VERSION 5.8 ;
BUSBITCHARS "[]" ;
DIVIDERCHAR "/" ;
UNITS
    DATABASE MICRONS 1000 ;
END UNITS

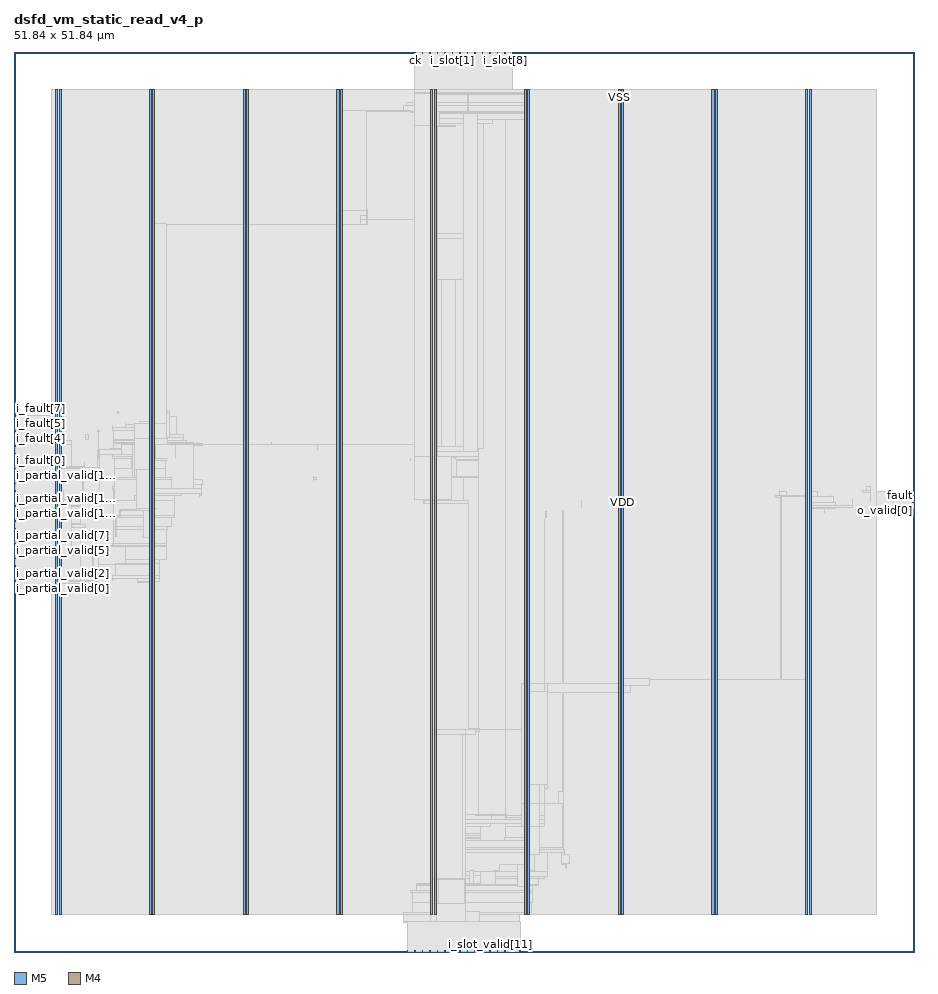
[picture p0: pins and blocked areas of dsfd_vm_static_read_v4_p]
MACRO dsfd_vm_static_read_v4_p
  FOREIGN dsfd_vm_static_read_v4_p 0 0 ;
  CLASS BLOCK ;
  SIZE 51.84 BY 51.84 ;
  PIN ck
    DIRECTION INPUT ;
    USE SIGNAL ;
    PORT
      LAYER M5 ;
        RECT  23.088 51.756 23.112 51.84 ;
    END
  END ck
  PIN fault
    DIRECTION OUTPUT ;
    USE SIGNAL ;
    PORT
      LAYER M4 ;
        RECT  51.756 26.304 51.84 26.328 ;
    END
  END fault
  PIN i_expected[0]
    DIRECTION INPUT ;
    USE SIGNAL ;
    PORT
      LAYER M5 ;
        RECT  23.952 51.756 23.976 51.84 ;
    END
  END i_expected[0]
  PIN i_expected[1]
    DIRECTION INPUT ;
    USE SIGNAL ;
    PORT
      LAYER M5 ;
        RECT  24.384 51.756 24.408 51.84 ;
    END
  END i_expected[1]
  PIN i_fault[0]
    DIRECTION INPUT ;
    USE SIGNAL ;
    PORT
      LAYER M4 ;
        RECT  0 27.84 0.084 27.864 ;
    END
  END i_fault[0]
  PIN i_fault[1]
    DIRECTION INPUT ;
    USE SIGNAL ;
    PORT
      LAYER M4 ;
        RECT  0 28.272 0.084 28.296 ;
    END
  END i_fault[1]
  PIN i_fault[2]
    DIRECTION INPUT ;
    USE SIGNAL ;
    PORT
      LAYER M4 ;
        RECT  0 28.704 0.084 28.728 ;
    END
  END i_fault[2]
  PIN i_fault[3]
    DIRECTION INPUT ;
    USE SIGNAL ;
    PORT
      LAYER M4 ;
        RECT  0 29.136 0.084 29.16 ;
    END
  END i_fault[3]
  PIN i_fault[4]
    DIRECTION INPUT ;
    USE SIGNAL ;
    PORT
      LAYER M4 ;
        RECT  0 29.568 0.084 29.592 ;
    END
  END i_fault[4]
  PIN i_fault[5]
    DIRECTION INPUT ;
    USE SIGNAL ;
    PORT
      LAYER M4 ;
        RECT  0 30 0.084 30.024 ;
    END
  END i_fault[5]
  PIN i_fault[6]
    DIRECTION INPUT ;
    USE SIGNAL ;
    PORT
      LAYER M4 ;
        RECT  0 30.432 0.084 30.456 ;
    END
  END i_fault[6]
  PIN i_fault[7]
    DIRECTION INPUT ;
    USE SIGNAL ;
    PORT
      LAYER M4 ;
        RECT  0 30.864 0.084 30.888 ;
    END
  END i_fault[7]
  PIN i_partial_valid[0]
    DIRECTION INPUT ;
    USE SIGNAL ;
    PORT
      LAYER M4 ;
        RECT  0 20.928 0.084 20.952 ;
    END
  END i_partial_valid[0]
  PIN i_partial_valid[10]
    DIRECTION INPUT ;
    USE SIGNAL ;
    PORT
      LAYER M4 ;
        RECT  0 25.248 0.084 25.272 ;
    END
  END i_partial_valid[10]
  PIN i_partial_valid[11]
    DIRECTION INPUT ;
    USE SIGNAL ;
    PORT
      LAYER M4 ;
        RECT  0 25.68 0.084 25.704 ;
    END
  END i_partial_valid[11]
  PIN i_partial_valid[12]
    DIRECTION INPUT ;
    USE SIGNAL ;
    PORT
      LAYER M4 ;
        RECT  0 26.112 0.084 26.136 ;
    END
  END i_partial_valid[12]
  PIN i_partial_valid[13]
    DIRECTION INPUT ;
    USE SIGNAL ;
    PORT
      LAYER M4 ;
        RECT  0 26.544 0.084 26.568 ;
    END
  END i_partial_valid[13]
  PIN i_partial_valid[14]
    DIRECTION INPUT ;
    USE SIGNAL ;
    PORT
      LAYER M4 ;
        RECT  0 26.976 0.084 27 ;
    END
  END i_partial_valid[14]
  PIN i_partial_valid[15]
    DIRECTION INPUT ;
    USE SIGNAL ;
    PORT
      LAYER M4 ;
        RECT  0 27.408 0.084 27.432 ;
    END
  END i_partial_valid[15]
  PIN i_partial_valid[1]
    DIRECTION INPUT ;
    USE SIGNAL ;
    PORT
      LAYER M4 ;
        RECT  0 21.36 0.084 21.384 ;
    END
  END i_partial_valid[1]
  PIN i_partial_valid[2]
    DIRECTION INPUT ;
    USE SIGNAL ;
    PORT
      LAYER M4 ;
        RECT  0 21.792 0.084 21.816 ;
    END
  END i_partial_valid[2]
  PIN i_partial_valid[3]
    DIRECTION INPUT ;
    USE SIGNAL ;
    PORT
      LAYER M4 ;
        RECT  0 22.224 0.084 22.248 ;
    END
  END i_partial_valid[3]
  PIN i_partial_valid[4]
    DIRECTION INPUT ;
    USE SIGNAL ;
    PORT
      LAYER M4 ;
        RECT  0 22.656 0.084 22.68 ;
    END
  END i_partial_valid[4]
  PIN i_partial_valid[5]
    DIRECTION INPUT ;
    USE SIGNAL ;
    PORT
      LAYER M4 ;
        RECT  0 23.088 0.084 23.112 ;
    END
  END i_partial_valid[5]
  PIN i_partial_valid[6]
    DIRECTION INPUT ;
    USE SIGNAL ;
    PORT
      LAYER M4 ;
        RECT  0 23.52 0.084 23.544 ;
    END
  END i_partial_valid[6]
  PIN i_partial_valid[7]
    DIRECTION INPUT ;
    USE SIGNAL ;
    PORT
      LAYER M4 ;
        RECT  0 23.952 0.084 23.976 ;
    END
  END i_partial_valid[7]
  PIN i_partial_valid[8]
    DIRECTION INPUT ;
    USE SIGNAL ;
    PORT
      LAYER M4 ;
        RECT  0 24.384 0.084 24.408 ;
    END
  END i_partial_valid[8]
  PIN i_partial_valid[9]
    DIRECTION INPUT ;
    USE SIGNAL ;
    PORT
      LAYER M4 ;
        RECT  0 24.816 0.084 24.84 ;
    END
  END i_partial_valid[9]
  PIN i_slot[0]
    DIRECTION INPUT ;
    USE SIGNAL ;
    PORT
      LAYER M5 ;
        RECT  24.816 51.756 24.84 51.84 ;
    END
  END i_slot[0]
  PIN i_slot[1]
    DIRECTION INPUT ;
    USE SIGNAL ;
    PORT
      LAYER M5 ;
        RECT  25.248 51.756 25.272 51.84 ;
    END
  END i_slot[1]
  PIN i_slot[2]
    DIRECTION INPUT ;
    USE SIGNAL ;
    PORT
      LAYER M5 ;
        RECT  25.68 51.756 25.704 51.84 ;
    END
  END i_slot[2]
  PIN i_slot[3]
    DIRECTION INPUT ;
    USE SIGNAL ;
    PORT
      LAYER M5 ;
        RECT  26.112 51.756 26.136 51.84 ;
    END
  END i_slot[3]
  PIN i_slot[4]
    DIRECTION INPUT ;
    USE SIGNAL ;
    PORT
      LAYER M5 ;
        RECT  26.544 51.756 26.568 51.84 ;
    END
  END i_slot[4]
  PIN i_slot[5]
    DIRECTION INPUT ;
    USE SIGNAL ;
    PORT
      LAYER M5 ;
        RECT  26.976 51.756 27 51.84 ;
    END
  END i_slot[5]
  PIN i_slot[6]
    DIRECTION INPUT ;
    USE SIGNAL ;
    PORT
      LAYER M5 ;
        RECT  27.408 51.756 27.432 51.84 ;
    END
  END i_slot[6]
  PIN i_slot[7]
    DIRECTION INPUT ;
    USE SIGNAL ;
    PORT
      LAYER M5 ;
        RECT  27.84 51.756 27.864 51.84 ;
    END
  END i_slot[7]
  PIN i_slot[8]
    DIRECTION INPUT ;
    USE SIGNAL ;
    PORT
      LAYER M5 ;
        RECT  28.272 51.756 28.296 51.84 ;
    END
  END i_slot[8]
  PIN i_slot[9]
    DIRECTION INPUT ;
    USE SIGNAL ;
    PORT
      LAYER M5 ;
        RECT  28.704 51.756 28.728 51.84 ;
    END
  END i_slot[9]
  PIN i_slot_valid[0]
    DIRECTION INPUT ;
    USE SIGNAL ;
    PORT
      LAYER M5 ;
        RECT  22.656 0 22.68 0.084 ;
    END
  END i_slot_valid[0]
  PIN i_slot_valid[10]
    DIRECTION INPUT ;
    USE SIGNAL ;
    PORT
      LAYER M5 ;
        RECT  26.976 0 27 0.084 ;
    END
  END i_slot_valid[10]
  PIN i_slot_valid[11]
    DIRECTION INPUT ;
    USE SIGNAL ;
    PORT
      LAYER M5 ;
        RECT  27.408 0 27.432 0.084 ;
    END
  END i_slot_valid[11]
  PIN i_slot_valid[12]
    DIRECTION INPUT ;
    USE SIGNAL ;
    PORT
      LAYER M5 ;
        RECT  27.84 0 27.864 0.084 ;
    END
  END i_slot_valid[12]
  PIN i_slot_valid[13]
    DIRECTION INPUT ;
    USE SIGNAL ;
    PORT
      LAYER M5 ;
        RECT  28.272 0 28.296 0.084 ;
    END
  END i_slot_valid[13]
  PIN i_slot_valid[14]
    DIRECTION INPUT ;
    USE SIGNAL ;
    PORT
      LAYER M5 ;
        RECT  28.704 0 28.728 0.084 ;
    END
  END i_slot_valid[14]
  PIN i_slot_valid[15]
    DIRECTION INPUT ;
    USE SIGNAL ;
    PORT
      LAYER M5 ;
        RECT  29.136 0 29.16 0.084 ;
    END
  END i_slot_valid[15]
  PIN i_slot_valid[1]
    DIRECTION INPUT ;
    USE SIGNAL ;
    PORT
      LAYER M5 ;
        RECT  23.088 0 23.112 0.084 ;
    END
  END i_slot_valid[1]
  PIN i_slot_valid[2]
    DIRECTION INPUT ;
    USE SIGNAL ;
    PORT
      LAYER M5 ;
        RECT  23.52 0 23.544 0.084 ;
    END
  END i_slot_valid[2]
  PIN i_slot_valid[3]
    DIRECTION INPUT ;
    USE SIGNAL ;
    PORT
      LAYER M5 ;
        RECT  23.952 0 23.976 0.084 ;
    END
  END i_slot_valid[3]
  PIN i_slot_valid[4]
    DIRECTION INPUT ;
    USE SIGNAL ;
    PORT
      LAYER M5 ;
        RECT  24.384 0 24.408 0.084 ;
    END
  END i_slot_valid[4]
  PIN i_slot_valid[5]
    DIRECTION INPUT ;
    USE SIGNAL ;
    PORT
      LAYER M5 ;
        RECT  24.816 0 24.84 0.084 ;
    END
  END i_slot_valid[5]
  PIN i_slot_valid[6]
    DIRECTION INPUT ;
    USE SIGNAL ;
    PORT
      LAYER M5 ;
        RECT  25.248 0 25.272 0.084 ;
    END
  END i_slot_valid[6]
  PIN i_slot_valid[7]
    DIRECTION INPUT ;
    USE SIGNAL ;
    PORT
      LAYER M5 ;
        RECT  25.68 0 25.704 0.084 ;
    END
  END i_slot_valid[7]
  PIN i_slot_valid[8]
    DIRECTION INPUT ;
    USE SIGNAL ;
    PORT
      LAYER M5 ;
        RECT  26.112 0 26.136 0.084 ;
    END
  END i_slot_valid[8]
  PIN i_slot_valid[9]
    DIRECTION INPUT ;
    USE SIGNAL ;
    PORT
      LAYER M5 ;
        RECT  26.544 0 26.568 0.084 ;
    END
  END i_slot_valid[9]
  PIN o_valid[0]
    DIRECTION OUTPUT ;
    USE SIGNAL ;
    PORT
      LAYER M4 ;
        RECT  51.756 25.44 51.84 25.464 ;
    END
  END o_valid[0]
  PIN o_valid[1]
    DIRECTION OUTPUT ;
    USE SIGNAL ;
    PORT
      LAYER M4 ;
        RECT  51.756 25.872 51.84 25.896 ;
    END
  END o_valid[1]
  PIN rst_n
    DIRECTION INPUT ;
    USE SIGNAL ;
    PORT
      LAYER M5 ;
        RECT  23.52 51.756 23.544 51.84 ;
    END
  END rst_n
  PIN VDD
    DIRECTION INOUT ;
    USE POWER ;
    PORT
      LAYER M5 ;
        RECT  45.792 2.151 45.912 49.689 ;
        RECT  40.392 2.151 40.512 49.689 ;
        RECT  34.992 2.151 35.112 49.689 ;
        RECT  29.592 2.151 29.712 49.689 ;
        RECT  24.192 2.151 24.312 49.689 ;
        RECT  18.792 2.151 18.912 49.689 ;
        RECT  13.392 2.151 13.512 49.689 ;
        RECT  7.992 2.151 8.112 49.689 ;
        RECT  2.592 2.151 2.712 49.689 ;
    END
  END VDD
  PIN VSS
    DIRECTION INOUT ;
    USE GROUND ;
    PORT
      LAYER M5 ;
        RECT  45.6 2.137 45.72 49.703 ;
        RECT  40.2 2.137 40.32 49.703 ;
        RECT  34.8 2.137 34.92 49.703 ;
        RECT  29.4 2.137 29.52 49.703 ;
        RECT  24 2.137 24.12 49.703 ;
        RECT  18.6 2.137 18.72 49.703 ;
        RECT  13.2 2.137 13.32 49.703 ;
        RECT  7.8 2.137 7.92 49.703 ;
        RECT  2.4 2.137 2.52 49.703 ;
    END
  END VSS
  # OT_OBS_CLOSED layer=M5 d_um=1.536 added=10
  OBS
    LAYER RVTN ;
     RECT  2.16 2.16 49.68 2.295 ;
     RECT  2.16 2.565 49.68 2.835 ;
     RECT  2.16 3.105 49.68 3.375 ;
     RECT  2.16 3.645 49.68 3.915 ;
     RECT  2.16 4.185 49.68 4.455 ;
     RECT  2.16 4.725 49.68 4.995 ;
     RECT  2.16 5.265 49.68 5.535 ;
     RECT  2.16 5.805 49.68 6.075 ;
     RECT  2.16 6.345 49.68 6.615 ;
     RECT  2.16 6.885 49.68 7.155 ;
     RECT  2.16 7.425 49.68 7.695 ;
     RECT  2.16 7.965 49.68 8.235 ;
     RECT  2.16 8.505 49.68 8.775 ;
     RECT  2.16 9.045 49.68 9.315 ;
     RECT  2.16 9.585 49.68 9.855 ;
     RECT  2.16 10.125 49.68 10.395 ;
     RECT  2.16 10.665 49.68 10.935 ;
     RECT  2.16 11.205 49.68 11.475 ;
     RECT  2.16 11.745 49.68 12.015 ;
     RECT  2.16 12.285 49.68 12.555 ;
     RECT  2.16 12.825 49.68 13.095 ;
     RECT  2.16 13.365 49.68 13.635 ;
     RECT  2.16 13.905 49.68 14.175 ;
     RECT  2.16 14.445 49.68 14.715 ;
     RECT  2.16 14.985 49.68 15.255 ;
     RECT  2.16 15.525 49.68 15.795 ;
     RECT  2.16 16.065 49.68 16.335 ;
     RECT  2.16 16.605 49.68 16.875 ;
     RECT  2.16 17.145 49.68 17.415 ;
     RECT  2.16 17.685 49.68 17.955 ;
     RECT  2.16 18.225 49.68 18.495 ;
     RECT  2.16 18.765 49.68 19.035 ;
     RECT  2.16 19.305 49.68 19.575 ;
     RECT  2.16 19.845 49.68 20.115 ;
     RECT  2.16 20.385 49.68 20.655 ;
     RECT  2.16 20.925 49.68 21.195 ;
     RECT  2.16 21.465 49.68 21.735 ;
     RECT  2.16 22.005 49.68 22.275 ;
     RECT  2.16 22.545 49.68 22.815 ;
     RECT  2.16 23.085 49.68 23.355 ;
     RECT  2.16 23.625 49.68 23.895 ;
     RECT  2.16 24.165 49.68 24.435 ;
     RECT  2.16 24.705 49.68 24.975 ;
     RECT  2.16 25.245 49.68 25.515 ;
     RECT  2.16 25.785 49.68 26.055 ;
     RECT  2.16 26.325 49.68 26.595 ;
     RECT  2.16 26.865 49.68 27.135 ;
     RECT  2.16 27.405 49.68 27.675 ;
     RECT  2.16 27.945 49.68 28.215 ;
     RECT  2.16 28.485 49.68 28.755 ;
     RECT  2.16 29.025 49.68 29.295 ;
     RECT  2.16 29.565 49.68 29.835 ;
     RECT  2.16 30.105 49.68 30.375 ;
     RECT  2.16 30.645 49.68 30.915 ;
     RECT  2.16 31.185 49.68 31.455 ;
     RECT  2.16 31.725 49.68 31.995 ;
     RECT  2.16 32.265 49.68 32.535 ;
     RECT  2.16 32.805 49.68 33.075 ;
     RECT  2.16 33.345 49.68 33.615 ;
     RECT  2.16 33.885 49.68 34.155 ;
     RECT  2.16 34.425 49.68 34.695 ;
     RECT  2.16 34.965 49.68 35.235 ;
     RECT  2.16 35.505 49.68 35.775 ;
     RECT  2.16 36.045 49.68 36.315 ;
     RECT  2.16 36.585 49.68 36.855 ;
     RECT  2.16 37.125 49.68 37.395 ;
     RECT  2.16 37.665 49.68 37.935 ;
     RECT  2.16 38.205 49.68 38.475 ;
     RECT  2.16 38.745 49.68 39.015 ;
     RECT  2.16 39.285 49.68 39.555 ;
     RECT  2.16 39.825 49.68 40.095 ;
     RECT  2.16 40.365 49.68 40.635 ;
     RECT  2.16 40.905 49.68 41.175 ;
     RECT  2.16 41.445 49.68 41.715 ;
     RECT  2.16 41.985 49.68 42.255 ;
     RECT  2.16 42.525 49.68 42.795 ;
     RECT  2.16 43.065 49.68 43.335 ;
     RECT  2.16 43.605 49.68 43.875 ;
     RECT  2.16 44.145 49.68 44.415 ;
     RECT  2.16 44.685 49.68 44.955 ;
     RECT  2.16 45.225 49.68 45.495 ;
     RECT  2.16 45.765 49.68 46.035 ;
     RECT  2.16 46.305 49.68 46.575 ;
     RECT  2.16 46.845 49.68 47.115 ;
     RECT  2.16 47.385 49.68 47.655 ;
     RECT  2.16 47.925 49.68 48.195 ;
     RECT  2.16 48.465 49.68 48.735 ;
     RECT  2.16 49.005 49.68 49.275 ;
     RECT  2.16 49.545 49.68 49.68 ;
    LAYER RVTP ;
     RECT  2.16 2.295 49.68 2.565 ;
     RECT  2.16 2.835 49.68 3.105 ;
     RECT  2.16 3.375 49.68 3.645 ;
     RECT  2.16 3.915 49.68 4.185 ;
     RECT  2.16 4.455 49.68 4.725 ;
     RECT  2.16 4.995 49.68 5.265 ;
     RECT  2.16 5.535 49.68 5.805 ;
     RECT  2.16 6.075 49.68 6.345 ;
     RECT  2.16 6.615 49.68 6.885 ;
     RECT  2.16 7.155 49.68 7.425 ;
     RECT  2.16 7.695 49.68 7.965 ;
     RECT  2.16 8.235 49.68 8.505 ;
     RECT  2.16 8.775 49.68 9.045 ;
     RECT  2.16 9.315 49.68 9.585 ;
     RECT  2.16 9.855 49.68 10.125 ;
     RECT  2.16 10.395 49.68 10.665 ;
     RECT  2.16 10.935 49.68 11.205 ;
     RECT  2.16 11.475 49.68 11.745 ;
     RECT  2.16 12.015 49.68 12.285 ;
     RECT  2.16 12.555 49.68 12.825 ;
     RECT  2.16 13.095 49.68 13.365 ;
     RECT  2.16 13.635 49.68 13.905 ;
     RECT  2.16 14.175 49.68 14.445 ;
     RECT  2.16 14.715 49.68 14.985 ;
     RECT  2.16 15.255 49.68 15.525 ;
     RECT  2.16 15.795 49.68 16.065 ;
     RECT  2.16 16.335 49.68 16.605 ;
     RECT  2.16 16.875 49.68 17.145 ;
     RECT  2.16 17.415 49.68 17.685 ;
     RECT  2.16 17.955 49.68 18.225 ;
     RECT  2.16 18.495 49.68 18.765 ;
     RECT  2.16 19.035 49.68 19.305 ;
     RECT  2.16 19.575 49.68 19.845 ;
     RECT  2.16 20.115 49.68 20.385 ;
     RECT  2.16 20.655 49.68 20.925 ;
     RECT  2.16 21.195 49.68 21.465 ;
     RECT  2.16 21.735 49.68 22.005 ;
     RECT  2.16 22.275 49.68 22.545 ;
     RECT  2.16 22.815 49.68 23.085 ;
     RECT  2.16 23.355 49.68 23.625 ;
     RECT  2.16 23.895 49.68 24.165 ;
     RECT  2.16 24.435 49.68 24.705 ;
     RECT  2.16 24.975 49.68 25.245 ;
     RECT  2.16 25.515 49.68 25.785 ;
     RECT  2.16 26.055 49.68 26.325 ;
     RECT  2.16 26.595 49.68 26.865 ;
     RECT  2.16 27.135 49.68 27.405 ;
     RECT  2.16 27.675 49.68 27.945 ;
     RECT  2.16 28.215 49.68 28.485 ;
     RECT  2.16 28.755 49.68 29.025 ;
     RECT  2.16 29.295 49.68 29.565 ;
     RECT  2.16 29.835 49.68 30.105 ;
     RECT  2.16 30.375 49.68 30.645 ;
     RECT  2.16 30.915 49.68 31.185 ;
     RECT  2.16 31.455 49.68 31.725 ;
     RECT  2.16 31.995 49.68 32.265 ;
     RECT  2.16 32.535 49.68 32.805 ;
     RECT  2.16 33.075 49.68 33.345 ;
     RECT  2.16 33.615 49.68 33.885 ;
     RECT  2.16 34.155 49.68 34.425 ;
     RECT  2.16 34.695 49.68 34.965 ;
     RECT  2.16 35.235 49.68 35.505 ;
     RECT  2.16 35.775 49.68 36.045 ;
     RECT  2.16 36.315 49.68 36.585 ;
     RECT  2.16 36.855 49.68 37.125 ;
     RECT  2.16 37.395 49.68 37.665 ;
     RECT  2.16 37.935 49.68 38.205 ;
     RECT  2.16 38.475 49.68 38.745 ;
     RECT  2.16 39.015 49.68 39.285 ;
     RECT  2.16 39.555 49.68 39.825 ;
     RECT  2.16 40.095 49.68 40.365 ;
     RECT  2.16 40.635 49.68 40.905 ;
     RECT  2.16 41.175 49.68 41.445 ;
     RECT  2.16 41.715 49.68 41.985 ;
     RECT  2.16 42.255 49.68 42.525 ;
     RECT  2.16 42.795 49.68 43.065 ;
     RECT  2.16 43.335 49.68 43.605 ;
     RECT  2.16 43.875 49.68 44.145 ;
     RECT  2.16 44.415 49.68 44.685 ;
     RECT  2.16 44.955 49.68 45.225 ;
     RECT  2.16 45.495 49.68 45.765 ;
     RECT  2.16 46.035 49.68 46.305 ;
     RECT  2.16 46.575 49.68 46.845 ;
     RECT  2.16 47.115 49.68 47.385 ;
     RECT  2.16 47.655 49.68 47.925 ;
     RECT  2.16 48.195 49.68 48.465 ;
     RECT  2.16 48.735 49.68 49.005 ;
     RECT  2.16 49.275 49.68 49.545 ;
    LAYER M1 ;
     RECT  2.16 2.151 49.68 49.689 ;
    LAYER M2 ;
     RECT  0.535 23.904 2.16 23.922 ;
     RECT  2.16 2.151 49.68 49.689 ;
     RECT  49.68 25.416 50.711 26.514 ;
    LAYER M3 ;
     RECT  23.94 0.571 23.958 1.723 ;
     RECT  25.668 0.571 25.686 1.723 ;
     RECT  22.428 1.723 29.142 2.143 ;
     RECT  22.428 2.143 29.505 2.255 ;
     RECT  22.932 2.255 29.505 2.263 ;
     RECT  2.415 2.143 2.505 2.413 ;
     RECT  7.815 2.143 7.905 2.413 ;
     RECT  13.215 2.143 13.305 2.413 ;
     RECT  18.615 2.143 18.705 2.413 ;
     RECT  34.815 2.143 34.905 2.413 ;
     RECT  40.215 2.143 40.305 2.413 ;
     RECT  45.615 2.143 45.705 2.413 ;
     RECT  22.932 2.263 29.79 2.839 ;
     RECT  22.932 2.839 29.862 3.451 ;
     RECT  22.824 3.451 29.862 3.569 ;
     RECT  23.184 3.569 29.862 3.811 ;
     RECT  23.184 3.811 30.222 3.875 ;
     RECT  23.184 3.875 26.874 3.947 ;
     RECT  23.616 3.947 26.874 3.965 ;
     RECT  27.72 3.875 30.222 4.261 ;
     RECT  27.72 4.261 30.546 4.351 ;
     RECT  24.015 3.965 26.874 4.415 ;
     RECT  25.128 4.415 26.874 4.621 ;
     RECT  27.72 4.351 30.726 4.621 ;
     RECT  31.788 4.801 31.806 5.035 ;
     RECT  31.536 5.035 31.806 5.071 ;
     RECT  31.536 5.071 31.986 5.603 ;
     RECT  25.128 4.621 30.726 5.729 ;
     RECT  25.236 5.729 30.726 5.737 ;
     RECT  31.536 5.603 31.698 5.737 ;
     RECT  25.236 5.737 31.698 5.909 ;
     RECT  25.236 5.909 31.626 5.999 ;
     RECT  25.236 5.999 30.222 6.035 ;
     RECT  31.14 5.999 31.626 6.035 ;
     RECT  25.308 6.035 30.222 6.413 ;
     RECT  25.308 6.413 26.91 6.449 ;
     RECT  25.308 6.449 26.874 6.539 ;
     RECT  25.524 6.539 26.874 6.575 ;
     RECT  28.224 6.413 30.222 6.611 ;
     RECT  25.812 6.575 26.874 6.683 ;
     RECT  25.848 6.683 26.874 6.809 ;
     RECT  25.884 6.809 26.874 7.231 ;
     RECT  28.296 6.611 30.222 7.231 ;
     RECT  25.884 7.231 27.45 7.393 ;
     RECT  28.296 7.231 30.546 7.393 ;
     RECT  25.884 7.393 30.546 7.619 ;
     RECT  28.296 7.619 30.546 7.889 ;
     RECT  25.884 7.619 27.522 7.925 ;
     RECT  27.504 7.925 27.522 7.961 ;
     RECT  31.608 6.035 31.626 8.539 ;
     RECT  31.356 8.539 31.626 9.239 ;
     RECT  30.528 7.889 30.546 9.391 ;
     RECT  30.528 9.391 30.726 9.677 ;
     RECT  25.884 7.925 26.73 12.715 ;
     RECT  25.884 12.715 26.802 12.845 ;
     RECT  34.815 2.413 35.097 14.971 ;
     RECT  36.576 15.331 36.594 15.389 ;
     RECT  34.815 14.971 35.478 15.725 ;
     RECT  2.415 2.413 2.697 20.923 ;
     RECT  2.304 20.923 2.697 21.155 ;
     RECT  2.412 21.155 2.697 21.235 ;
     RECT  3.816 21.199 3.834 21.235 ;
     RECT  7.815 2.413 8.097 21.271 ;
     RECT  2.412 21.235 4.122 21.355 ;
     RECT  7.092 21.271 8.097 21.361 ;
     RECT  2.412 21.355 4.842 21.389 ;
     RECT  2.412 21.389 2.697 21.425 ;
     RECT  4.824 21.389 4.842 21.425 ;
     RECT  5.652 21.397 5.67 21.433 ;
     RECT  5.652 21.433 5.814 21.541 ;
     RECT  7.092 21.361 8.37 21.541 ;
     RECT  5.652 21.541 8.37 21.695 ;
     RECT  2.415 21.425 2.697 22.219 ;
     RECT  5.868 21.695 8.37 22.349 ;
     RECT  6.408 22.349 8.37 22.621 ;
     RECT  2.304 22.219 2.697 22.855 ;
     RECT  3.816 21.389 3.834 22.855 ;
     RECT  2.304 22.855 4.122 22.891 ;
     RECT  2.304 22.891 4.842 22.925 ;
     RECT  3.816 22.925 4.842 23.009 ;
     RECT  4.824 23.009 4.842 23.161 ;
     RECT  2.304 22.925 2.697 23.315 ;
     RECT  4.824 23.161 5.418 23.351 ;
     RECT  5.4 23.351 5.418 23.371 ;
     RECT  6.408 22.621 8.766 23.371 ;
     RECT  5.4 23.371 8.766 23.41 ;
     RECT  5.688 23.41 8.766 23.549 ;
     RECT  0.54 23.899 0.558 23.981 ;
     RECT  5.724 23.549 8.766 24.331 ;
     RECT  2.415 23.315 2.697 24.367 ;
     RECT  2.304 24.367 2.697 24.469 ;
     RECT  3.816 23.009 3.834 24.469 ;
     RECT  2.304 24.469 3.834 24.475 ;
     RECT  5.724 24.331 8.838 24.511 ;
     RECT  2.304 24.475 4.122 24.629 ;
     RECT  2.304 24.629 3.834 24.665 ;
     RECT  30.528 9.677 30.546 24.899 ;
     RECT  2.304 24.665 2.697 24.935 ;
     RECT  5.724 24.511 9.054 25.015 ;
     RECT  5.688 25.015 9.054 25.051 ;
     RECT  4.86 25.045 4.878 25.085 ;
     RECT  5.688 25.051 9.234 25.169 ;
     RECT  30.636 25.051 30.654 25.349 ;
     RECT  31.608 9.239 31.626 25.439 ;
     RECT  48.456 25.411 48.474 25.511 ;
     RECT  45.615 2.413 45.897 25.519 ;
     RECT  46.692 25.321 46.71 25.519 ;
     RECT  45.615 25.519 47.322 25.531 ;
     RECT  45.54 25.531 47.322 25.591 ;
     RECT  2.415 24.935 2.697 25.675 ;
     RECT  3.816 24.665 3.834 25.675 ;
     RECT  2.304 25.675 3.834 25.745 ;
     RECT  45.54 25.591 48.294 25.745 ;
     RECT  45.54 25.745 47.322 25.889 ;
     RECT  5.724 25.169 9.234 25.979 ;
     RECT  32.688 25.591 32.706 25.979 ;
     RECT  2.415 25.745 3.834 26.051 ;
     RECT  48.276 25.745 48.294 26.051 ;
     RECT  24.015 4.415 24.297 26.053 ;
     RECT  24.015 26.053 24.93 26.093 ;
     RECT  3.816 26.051 3.834 26.095 ;
     RECT  3.816 26.095 4.194 26.159 ;
     RECT  45.54 25.889 47.214 26.237 ;
     RECT  43.956 26.203 43.974 26.248 ;
     RECT  3.96 26.159 4.194 26.249 ;
     RECT  45.615 26.237 47.214 26.249 ;
     RECT  43.956 26.248 44.658 26.251 ;
     RECT  6.948 25.979 9.234 26.285 ;
     RECT  43.884 26.251 44.658 26.285 ;
     RECT  47.016 26.249 47.034 26.285 ;
     RECT  43.884 26.285 44.514 26.291 ;
     RECT  7.092 26.285 9.234 26.293 ;
     RECT  10.656 26.257 10.674 26.293 ;
     RECT  7.092 26.293 9.63 26.401 ;
     RECT  10.656 26.293 10.818 26.401 ;
     RECT  49.32 25.951 49.338 26.491 ;
     RECT  44.1 26.291 44.514 26.519 ;
     RECT  45.615 26.249 46.278 26.519 ;
     RECT  50.688 25.411 50.706 26.519 ;
     RECT  44.1 26.519 44.118 26.555 ;
     RECT  2.415 26.051 2.826 26.573 ;
     RECT  48.888 26.491 49.338 26.591 ;
     RECT  5.724 25.979 5.814 26.635 ;
     RECT  7.092 26.401 10.818 26.699 ;
     RECT  4.86 26.671 4.878 26.717 ;
     RECT  5.688 26.635 5.814 26.789 ;
     RECT  49.104 26.591 49.338 26.789 ;
     RECT  10.332 26.699 10.818 26.941 ;
     RECT  2.415 26.573 2.697 26.971 ;
     RECT  2.304 26.971 2.697 27.095 ;
     RECT  5.796 26.789 5.814 27.211 ;
     RECT  7.092 26.699 9.09 27.211 ;
     RECT  17.244 27.175 17.262 27.211 ;
     RECT  10.332 26.941 10.854 27.239 ;
     RECT  24.015 26.093 24.642 27.307 ;
     RECT  25.884 12.845 26.73 27.307 ;
     RECT  5.796 27.211 9.09 27.329 ;
     RECT  17.244 27.211 17.406 27.329 ;
     RECT  17.244 27.329 17.262 27.365 ;
     RECT  24.015 27.307 26.73 27.365 ;
     RECT  3.96 26.249 3.978 27.373 ;
     RECT  5.796 27.329 8.73 27.821 ;
     RECT  2.34 27.095 2.697 27.835 ;
     RECT  2.304 27.835 2.697 27.877 ;
     RECT  3.888 27.373 3.978 27.877 ;
     RECT  2.304 27.877 4.086 27.941 ;
     RECT  4.068 27.941 4.086 28.175 ;
     RECT  7.815 27.821 8.73 28.291 ;
     RECT  25.488 27.365 26.73 28.291 ;
     RECT  25.488 28.291 26.766 28.381 ;
     RECT  7.815 28.291 8.802 28.409 ;
     RECT  5.796 27.821 6.786 28.417 ;
     RECT  22.824 28.291 22.842 28.445 ;
     RECT  4.824 27.883 4.842 28.493 ;
     RECT  5.652 28.417 6.786 28.561 ;
     RECT  24.015 27.365 24.642 28.561 ;
     RECT  25.416 28.381 26.766 28.561 ;
     RECT  24.015 28.561 26.766 28.823 ;
     RECT  5.652 28.561 6.93 28.831 ;
     RECT  5.544 28.831 6.93 28.985 ;
     RECT  26.712 28.823 26.766 29.029 ;
     RECT  24.015 28.823 25.902 29.093 ;
     RECT  10.332 27.239 10.35 29.191 ;
     RECT  7.815 28.409 8.154 29.227 ;
     RECT  2.304 27.941 3.294 29.255 ;
     RECT  17.46 28.921 17.478 29.255 ;
     RECT  5.724 28.985 6.93 29.263 ;
     RECT  7.815 29.227 8.19 29.263 ;
     RECT  9.288 28.453 9.306 29.263 ;
     RECT  10.332 29.191 10.854 29.263 ;
     RECT  9.288 29.263 10.854 29.291 ;
     RECT  9.288 29.291 10.35 29.299 ;
     RECT  8.964 29.299 10.35 29.327 ;
     RECT  14.832 29.263 14.85 29.363 ;
     RECT  5.724 29.263 8.19 29.371 ;
     RECT  8.964 29.327 9.918 29.371 ;
     RECT  2.415 29.255 3.294 29.489 ;
     RECT  5.724 29.371 9.918 29.489 ;
     RECT  5.724 29.489 7.002 29.525 ;
     RECT  4.14 29.497 4.158 29.533 ;
     RECT  7.815 29.489 9.738 29.645 ;
     RECT  4.14 29.533 4.302 29.795 ;
     RECT  8.964 29.645 9.738 29.831 ;
     RECT  2.415 29.489 2.697 29.995 ;
     RECT  4.86 29.995 4.878 30.035 ;
     RECT  5.724 29.525 6.966 30.037 ;
     RECT  5.652 30.037 6.966 30.209 ;
     RECT  5.652 30.209 5.67 30.335 ;
     RECT  6.408 30.209 6.966 30.407 ;
     RECT  2.34 29.995 2.697 30.415 ;
     RECT  7.815 29.645 8.097 30.415 ;
     RECT  6.408 30.407 6.426 30.443 ;
     RECT  2.304 30.415 2.697 30.461 ;
     RECT  7.236 30.415 8.097 30.569 ;
     RECT  8.964 29.831 9.378 30.839 ;
     RECT  2.415 30.461 2.697 30.847 ;
     RECT  2.415 30.847 2.826 30.893 ;
     RECT  8.964 30.839 8.982 30.955 ;
     RECT  8.928 30.955 8.982 30.956 ;
     RECT  7.815 30.569 8.097 30.991 ;
     RECT  8.928 30.956 8.946 30.991 ;
     RECT  7.815 30.991 8.946 31.109 ;
     RECT  5.976 30.991 5.994 31.145 ;
     RECT  24.015 29.093 24.642 38.713 ;
     RECT  25.452 29.093 25.902 38.713 ;
     RECT  24.015 38.713 25.902 41.083 ;
     RECT  23.4 41.083 25.902 41.369 ;
     RECT  20.304 41.899 20.322 42.187 ;
     RECT  19.944 42.187 20.322 42.449 ;
     RECT  20.304 42.449 20.322 42.749 ;
     RECT  26.712 29.029 27.054 47.695 ;
     RECT  24.015 41.369 25.902 47.731 ;
     RECT  26.712 47.695 27.378 47.731 ;
     RECT  26.712 47.731 27.558 47.965 ;
     RECT  28.296 7.889 29.697 47.965 ;
     RECT  23.472 47.731 25.902 48.001 ;
     RECT  23.148 48.001 25.902 48.271 ;
     RECT  26.712 47.965 29.697 48.271 ;
     RECT  23.148 48.271 29.697 48.361 ;
     RECT  22.824 48.361 29.697 48.427 ;
     RECT  22.428 48.427 29.697 48.731 ;
     RECT  22.608 48.731 29.697 48.929 ;
     RECT  23.4 48.929 29.697 49.379 ;
     RECT  2.415 30.893 2.697 49.427 ;
     RECT  7.815 31.109 8.097 49.427 ;
     RECT  13.215 2.413 13.497 49.427 ;
     RECT  18.615 2.413 18.897 49.427 ;
     RECT  23.472 49.379 29.697 49.427 ;
     RECT  34.815 15.725 35.097 49.427 ;
     RECT  40.215 2.413 40.497 49.427 ;
     RECT  45.615 26.519 45.897 49.427 ;
     RECT  23.472 49.427 29.505 49.469 ;
     RECT  23.472 49.469 25.578 49.565 ;
     RECT  26.496 49.469 29.505 49.565 ;
     RECT  23.688 49.565 25.578 49.577 ;
     RECT  26.856 49.565 27.306 49.577 ;
     RECT  28.152 49.565 29.505 49.577 ;
     RECT  2.415 49.427 2.505 49.697 ;
     RECT  7.815 49.427 7.905 49.697 ;
     RECT  13.215 49.427 13.305 49.697 ;
     RECT  18.615 49.427 18.705 49.697 ;
     RECT  23.94 49.577 24.105 49.697 ;
     RECT  29.415 49.577 29.505 49.697 ;
     RECT  34.815 49.427 34.905 49.697 ;
     RECT  40.215 49.427 40.305 49.697 ;
     RECT  45.615 49.427 45.705 49.697 ;
     RECT  23.94 49.697 23.958 49.853 ;
     RECT  27.288 49.577 27.306 50.189 ;
     RECT  25.56 49.577 25.578 50.765 ;
    LAYER M4 ;
     RECT  0.06 20.928 2.408 30.888 ;
     RECT  2.408 2.148 2.512 49.692 ;
     RECT  2.512 2.418 2.704 49.422 ;
     RECT  2.704 27.888 2.801 28.728 ;
     RECT  2.704 25.68 2.837 26.568 ;
     RECT  2.704 30.864 2.837 30.888 ;
     RECT  2.704 24.48 3.347 24.504 ;
     RECT  2.837 25.68 3.385 25.704 ;
     RECT  2.704 21.36 4.549 21.384 ;
     RECT  2.704 22.896 4.549 22.92 ;
     RECT  2.801 27.888 4.813 27.912 ;
     RECT  4.813 27.888 4.837 28.488 ;
     RECT  4.549 21.36 4.853 22.92 ;
     RECT  4.837 30 4.924 30.024 ;
     RECT  4.844 26.688 4.931 26.712 ;
     RECT  4.837 27.888 4.931 28.968 ;
     RECT  5.389 23.376 5.753 23.4 ;
     RECT  5.845 23.952 5.932 23.976 ;
     RECT  4.849 25.056 6.073 25.08 ;
     RECT  6.073 25.056 6.113 25.464 ;
     RECT  4.931 28.656 6.217 28.968 ;
     RECT  6.217 28.656 6.829 29.256 ;
     RECT  6.829 27.312 6.949 29.256 ;
     RECT  6.113 25.44 7.045 25.464 ;
     RECT  7.388 23.904 7.477 23.928 ;
     RECT  7.045 25.44 7.477 25.704 ;
     RECT  4.853 22.32 7.808 22.344 ;
     RECT  7.477 23.904 7.808 25.704 ;
     RECT  6.949 27.312 7.808 29.4 ;
     RECT  6.397 30.384 7.808 30.408 ;
     RECT  7.808 2.148 7.912 49.692 ;
     RECT  7.912 2.418 8.104 49.422 ;
     RECT  8.104 25.536 8.201 25.56 ;
     RECT  8.104 29.232 8.819 29.64 ;
     RECT  8.104 31.008 8.819 31.032 ;
     RECT  8.819 29.232 13.208 29.256 ;
     RECT  8.104 41.904 13.208 41.928 ;
     RECT  13.208 2.148 13.312 49.692 ;
     RECT  13.312 2.418 13.504 49.422 ;
     RECT  13.504 29.232 18.608 29.256 ;
     RECT  13.504 41.904 18.608 41.928 ;
     RECT  18.608 2.148 18.712 49.692 ;
     RECT  18.712 2.418 18.904 49.422 ;
     RECT  18.904 41.904 19.933 41.928 ;
     RECT  19.933 41.904 20.293 42.216 ;
     RECT  20.293 41.904 20.333 42.744 ;
     RECT  20.333 42.192 20.377 42.744 ;
     RECT  20.293 48.432 22.853 48.456 ;
     RECT  23.372 41.088 23.389 41.112 ;
     RECT  20.377 42.192 23.389 42.216 ;
     RECT  23.077 26.064 23.605 26.088 ;
     RECT  23.461 49.536 23.9 49.56 ;
     RECT  23.9 49.536 23.987 49.848 ;
     RECT  22.417 1.728 24.008 1.752 ;
     RECT  23.605 3.936 24.008 3.96 ;
     RECT  23.605 25.824 24.008 26.088 ;
     RECT  18.904 29.232 24.008 29.256 ;
     RECT  23.389 41.088 24.008 42.216 ;
     RECT  22.993 48.384 24.008 48.408 ;
     RECT  23.987 49.536 24.008 49.692 ;
     RECT  23.929 0.576 24.013 0.6 ;
     RECT  24.008 1.728 24.112 49.692 ;
     RECT  24.112 1.728 24.304 49.56 ;
     RECT  24.304 28.512 24.419 28.968 ;
     RECT  24.304 41.04 24.419 41.256 ;
     RECT  24.304 3.936 24.467 4.152 ;
     RECT  24.304 49.488 24.473 49.56 ;
     RECT  24.304 1.728 24.509 2.856 ;
     RECT  24.304 47.568 24.509 48.408 ;
     RECT  24.304 25.824 24.941 26.088 ;
     RECT  24.304 27.312 25.235 27.336 ;
     RECT  24.473 49.536 25.283 49.56 ;
     RECT  24.509 47.568 25.445 47.592 ;
     RECT  24.419 28.512 25.481 28.536 ;
     RECT  25.549 50.736 25.715 50.76 ;
     RECT  25.657 0.576 25.741 0.6 ;
     RECT  24.467 3.936 25.765 3.96 ;
     RECT  24.509 1.728 25.945 2.328 ;
     RECT  24.304 12.528 25.957 12.552 ;
     RECT  24.941 25.824 26.017 25.848 ;
     RECT  25.945 1.728 26.029 2.856 ;
     RECT  25.909 48.384 26.101 48.408 ;
     RECT  26.017 25.824 26.195 25.992 ;
     RECT  26.101 48.384 26.201 49.368 ;
     RECT  25.765 3.936 26.233 4.248 ;
     RECT  26.233 3.936 26.489 4.68 ;
     RECT  25.957 12.528 26.561 12.84 ;
     RECT  26.489 3.936 26.777 3.96 ;
     RECT  26.029 1.728 26.813 2.328 ;
     RECT  26.561 12.72 26.813 12.84 ;
     RECT  26.485 49.536 27.277 49.56 ;
     RECT  27.277 49.536 27.443 50.184 ;
     RECT  26.201 48.384 27.533 48.408 ;
     RECT  27.637 4.656 27.961 4.68 ;
     RECT  27.493 2.832 27.965 2.856 ;
     RECT  26.557 7.872 28.321 7.896 ;
     RECT  28.321 7.728 28.361 7.896 ;
     RECT  27.961 4.656 29.005 5.064 ;
     RECT  26.813 1.728 29.197 1.752 ;
     RECT  28.361 7.728 29.221 7.752 ;
     RECT  29.005 3.792 29.408 5.064 ;
     RECT  29.221 7.248 29.408 7.752 ;
     RECT  26.813 12.816 29.408 12.84 ;
     RECT  29.221 15.456 29.408 15.48 ;
     RECT  27.443 49.536 29.408 49.56 ;
     RECT  29.408 2.148 29.512 49.692 ;
     RECT  29.512 2.418 29.704 49.422 ;
     RECT  29.704 4.704 29.981 5.88 ;
     RECT  29.981 5.616 30.275 5.88 ;
     RECT  29.704 7.728 30.275 8.568 ;
     RECT  30.275 5.856 30.341 5.88 ;
     RECT  29.704 15.456 30.709 15.48 ;
     RECT  30.668 9.648 30.755 9.672 ;
     RECT  29.704 12.816 30.755 12.84 ;
     RECT  30.275 8.544 31.385 8.568 ;
     RECT  30.709 14.976 34.808 15.48 ;
     RECT  34.808 2.148 34.912 49.692 ;
     RECT  34.912 2.418 35.104 49.422 ;
     RECT  35.104 14.976 35.489 15.72 ;
     RECT  35.489 15.696 36.524 15.72 ;
     RECT  36.524 15.36 36.611 15.72 ;
     RECT  36.611 15.696 40.208 15.72 ;
     RECT  40.208 2.148 40.312 49.692 ;
     RECT  40.312 2.418 40.504 49.422 ;
     RECT  43.873 26.256 43.945 26.28 ;
     RECT  40.504 15.696 44.195 15.72 ;
     RECT  43.945 26.208 45.529 26.28 ;
     RECT  45.529 25.536 45.608 26.28 ;
     RECT  45.608 2.148 45.712 49.692 ;
     RECT  45.712 2.418 45.904 49.422 ;
     RECT  45.904 25.536 46.541 25.56 ;
     RECT  50.677 25.44 51.804 26.328 ;
    LAYER M5 ;
     RECT  22.656 0.016 29.16 1.763 ;
     RECT  2.4 2.137 2.52 2.151 ;
     RECT  7.8 2.137 7.92 2.151 ;
     RECT  13.2 2.137 13.32 2.151 ;
     RECT  18.6 2.137 18.72 2.151 ;
     RECT  29.4 2.137 29.52 2.151 ;
     RECT  34.8 2.137 34.92 2.151 ;
     RECT  40.2 2.137 40.32 2.151 ;
     RECT  45.6 2.137 45.72 2.151 ;
     RECT  24 1.763 24.312 2.821 ;
     RECT  24 2.821 24.456 4.163 ;
     RECT  25.968 2.821 25.992 4.213 ;
     RECT  29.4 2.151 29.712 5.605 ;
     RECT  29.4 5.605 30.264 7.237 ;
     RECT  29.232 7.237 30.264 8.579 ;
     RECT  24 4.163 24.312 12.517 ;
     RECT  25.824 4.213 25.992 12.517 ;
     RECT  24 12.517 25.992 12.805 ;
     RECT  30.72 9.637 30.744 15.011 ;
     RECT  29.232 8.579 29.712 15.491 ;
     RECT  36.576 15.349 36.6 15.731 ;
     RECT  2.4 2.151 2.712 22.885 ;
     RECT  4.56 21.349 4.584 22.931 ;
     RECT  7.8 2.151 8.112 23.893 ;
     RECT  5.856 23.941 5.88 25.091 ;
     RECT  7.44 23.893 8.112 25.429 ;
     RECT  7.2 25.429 8.112 25.573 ;
     RECT  2.4 22.885 3.336 25.715 ;
     RECT  24 12.805 26.184 25.813 ;
     RECT  23.616 25.813 26.184 26.003 ;
     RECT  23.616 26.003 25.224 26.053 ;
     RECT  44.16 15.685 44.184 26.243 ;
     RECT  7.056 25.573 8.112 27.781 ;
     RECT  4.896 26.677 4.92 27.923 ;
     RECT  23.088 26.053 25.224 28.547 ;
     RECT  6.96 27.781 8.112 29.605 ;
     RECT  4.848 28.453 4.872 30.035 ;
     RECT  6.96 29.605 8.808 30.419 ;
     RECT  7.8 30.419 8.808 41.939 ;
     RECT  23.088 28.547 24.408 47.603 ;
     RECT  20.304 42.709 20.328 48.467 ;
     RECT  23.088 47.603 24.312 49.477 ;
     RECT  23.088 49.477 24.408 49.525 ;
     RECT  26.112 49.333 26.136 49.525 ;
     RECT  29.4 15.491 29.712 49.525 ;
     RECT  2.4 25.715 2.712 49.689 ;
     RECT  7.8 41.939 8.112 49.689 ;
     RECT  13.2 2.151 13.512 49.689 ;
     RECT  18.6 2.151 18.912 49.689 ;
     RECT  23.088 49.525 29.712 49.689 ;
     RECT  34.8 2.151 35.112 49.689 ;
     RECT  40.2 2.151 40.512 49.689 ;
     RECT  45.6 2.151 45.912 49.689 ;
     RECT  2.4 49.689 2.52 49.703 ;
     RECT  7.8 49.689 7.92 49.703 ;
     RECT  13.2 49.689 13.32 49.703 ;
     RECT  18.6 49.689 18.72 49.703 ;
     RECT  23.088 49.689 29.52 49.703 ;
     RECT  34.8 49.689 34.92 49.703 ;
     RECT  40.2 49.689 40.32 49.703 ;
     RECT  45.6 49.689 45.72 49.703 ;
     RECT  23.088 49.703 28.728 51.792 ;
     RECT  24.312 1.763 25.992 2.821 ;
     RECT  24.456 2.821 25.968 4.163 ;
     RECT  24.312 4.163 25.968 4.213 ;
     RECT  24.312 4.213 25.824 12.517 ;
     RECT  29.712 8.579 30.264 9.637 ;
     RECT  29.712 9.637 30.72 15.011 ;
     RECT  35.112 15.349 36.576 15.731 ;
     RECT  44.184 15.685 45.6 26.243 ;
     RECT  3.336 22.885 4.56 22.931 ;
     RECT  18.912 42.709 20.304 48.467 ;
  END
END dsfd_vm_static_read_v4_p
END LIBRARY
